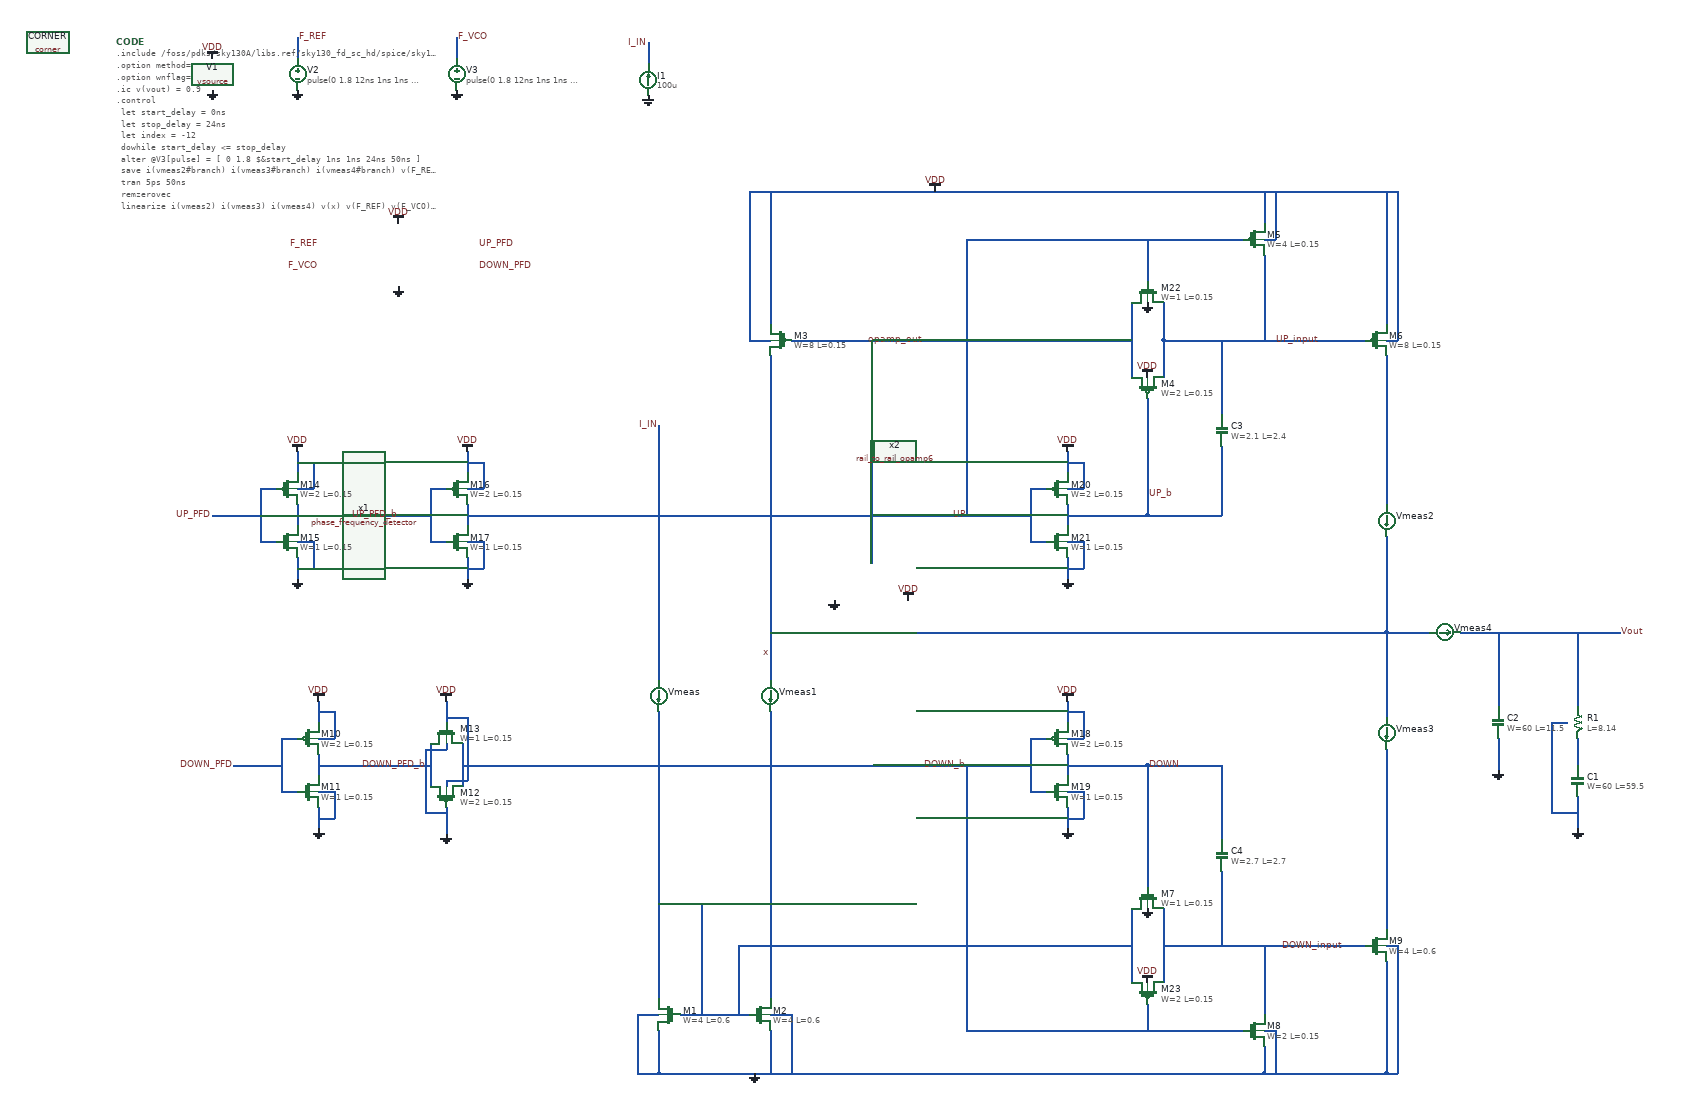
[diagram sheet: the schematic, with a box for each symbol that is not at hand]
v {xschem version=3.4.5 file_version=1.2
}
G {}
K {}
V {}
S {}
E {}
B 2 1210 -2170 2580 -1430 {flags=graph
y1=-0.00014
y2=0.00012
ypos1=0
ypos2=2
divy=5
subdivy=1
unity=1
x1=3.5340457e-07
x2=3.8858895e-07
divx=5
subdivx=1
xlabmag=1.0
ylabmag=1.0


dataset=0
unitx=1
logx=0
logy=0






color="11 5 6 12"
node="i(vmeas1)
i(vmeas2)
i(vmeas3)
\\"i(vmeas4)\\""
linewidth_mult=4
}
B 2 3350 -560 4770 220 {flags=graph
y1=-0.16
y2=1.9
ypos1=0
ypos2=2
divy=5
subdivy=1
unity=1
x1=3.5340457e-07
x2=3.8858895e-07
divx=5
subdivx=1
xlabmag=1.0
ylabmag=1.0


dataset=0
unitx=1
logx=0
logy=0








linewidth_mult=5





color="6 5"
node="up_pfd_b
down_pfd"}
B 2 3380 -1390 4760 -690 {flags=graph
y1=0
y2=0.01
ypos1=0
ypos2=2
divy=5
subdivy=1
unity=1
x1=3.5340457e-07
x2=3.8858895e-07
divx=5
subdivx=1
xlabmag=1.0
ylabmag=1.0


dataset=0
unitx=1
logx=0
logy=0








linewidth_mult=5

color="6 5"
node="up_pfd
down_pfd"}
B 2 4270 -2130 5120 -1470 {flags=graph
y1=0
y2=0.01
ypos1=0
ypos2=2
divy=5
subdivy=1
unity=1
x1=3.5340457e-07
x2=3.8858895e-07
divx=5
subdivx=1
xlabmag=1.0
ylabmag=1.0


dataset=0
unitx=1
logx=0
logy=0








linewidth_mult=5



color=6
node=vout}
B 2 2700 -2170 4070 -1430 {flags=graph
y1=0
y2=1.9
ypos1=0
ypos2=2
divy=5
subdivy=1
unity=1
x1=3.5340457e-07
x2=3.8858895e-07
divx=5
subdivx=1
xlabmag=1.0
ylabmag=1.0


dataset=0
unitx=1
logx=0
logy=0








linewidth_mult=4

color="6 7"
node="f_ref
f_vco"}
N 500 -1550 500 -1510 {
lab=F_REF}
N 800 -1550 800 -1510 {
lab=F_VCO}
N 1160 -1540 1160 -1500 {
lab=I_IN}
N 1220 290 1350 290 {
lab=#net1}
N 1180 320 1180 400 {
lab=GND}
N 1180 400 1680 400 {
lab=GND}
N 1140 290 1180 290 {
lab=GND}
N 1140 290 1140 400 {
lab=GND}
N 1140 400 1180 400 {
lab=GND}
N 1390 290 1430 290 {
lab=GND}
N 1350 -980 1390 -980 {
lab=VDD}
N 1680 400 1720 400 {
lab=GND}
N 1390 -1260 1390 -1010 {
lab=VDD}
N 1350 -1260 1350 -980 {
lab=VDD}
N 2550 -1260 2550 -1010 {
lab=VDD}
N 2320 -1260 2320 -1200 {
lab=VDD}
N 2320 -1170 2340 -1170 {
lab=VDD}
N 2340 -1260 2340 -1170 {
lab=VDD}
N 2570 -1260 2570 -980 {
lab=VDD}
N 2550 -980 2570 -980 {
lab=VDD}
N 2550 -950 2550 -670 {
lab=#net2}
N 1720 400 2320 400 {
lab=GND}
N 2320 350 2320 400 {
lab=GND}
N 2550 160 2570 160 {
lab=GND}
N 2550 400 2570 400 {
lab=GND}
N 600 -650 700 -650 {
lab=UP_PFD_b}
N 640 -180 750 -180 {
lab=DOWN_PFD_b}
N 340 -650 380 -650 {
lab=UP_PFD}
N 380 -180 420 -180 {
lab=DOWN_PFD}
N 1390 -950 1390 -550 {
lab=x}
N 1390 -430 1560 -430 {
lab=x}
N 1600 -430 2550 -430 {
lab=#net3}
N 1580 -980 1580 -560 {
lab=opamp_out}
N 2910 -230 2910 -180 {
lab=#net4}
N 2910 -430 2910 -290 {
lab=Vout}
N 2910 -120 2910 -60 {
lab=GND}
N 2860 -260 2890 -260 {
lab=GND}
N 2860 -260 2860 -90 {
lab=GND}
N 2860 -90 2910 -90 {
lab=GND}
N 2760 -430 2760 -290 {
lab=Vout}
N 2760 -230 2760 -170 {
lab=GND}
N 2690 -430 2990 -430 {
lab=Vout}
N 1260 80 1260 290 {
lab=#net1}
N 1180 80 1260 80 {
lab=#net1}
N 1430 290 1430 400 {
lab=GND}
N 1390 320 1390 400 {
lab=GND}
N 1330 160 2070 160 {
lab=#net1}
N 810 -180 1830 -180 {
lab=DOWN_b}
N 2100 -870 2100 -650 {
lab=UP_b}
N 1760 -1170 2280 -1170 {
lab=UP}
N 1760 -1170 1760 -650 {
lab=UP}
N 2320 -1140 2320 -980 {
lab=UP_input}
N 2130 -980 2510 -980 {
lab=UP_input}
N 1350 -1260 2570 -1260 {
lab=VDD}
N 2040 -180 2100 -180 {
lab=DOWN}
N 2100 -180 2100 50 {
lab=DOWN}
N 1760 -180 1760 320 {
lab=DOWN_b}
N 1760 320 2280 320 {
lab=DOWN_b}
N 750 -220 750 -140 {
lab=DOWN_PFD_b}
N 810 -220 810 -140 {
lab=DOWN_b}
N 780 -300 780 -260 {
lab=VDD}
N 780 -150 780 -140 {
lab=VDD}
N 780 -150 820 -150 {
lab=VDD}
N 820 -270 820 -150 {
lab=VDD}
N 780 -270 820 -270 {
lab=VDD}
N 780 -220 780 -210 {
lab=GND}
N 740 -210 780 -210 {
lab=GND}
N 740 -210 740 -90 {
lab=GND}
N 740 -90 780 -90 {
lab=GND}
N 780 -100 780 -50 {
lab=GND}
N 540 -200 540 -160 {
lab=DOWN_PFD_b}
N 470 -230 500 -230 {
lab=DOWN_PFD}
N 470 -230 470 -130 {
lab=DOWN_PFD}
N 470 -130 500 -130 {
lab=DOWN_PFD}
N 540 -180 640 -180 {
lab=DOWN_PFD_b}
N 420 -180 470 -180 {
lab=DOWN_PFD}
N 540 -100 540 -60 {
lab=GND}
N 540 -300 540 -260 {
lab=VDD}
N 540 -230 570 -230 {
lab=VDD}
N 570 -280 570 -230 {
lab=VDD}
N 540 -280 570 -280 {
lab=VDD}
N 540 -130 570 -130 {
lab=GND}
N 570 -130 570 -80 {
lab=GND}
N 540 -80 570 -80 {
lab=GND}
N 500 -670 500 -630 {
lab=UP_PFD_b}
N 430 -700 460 -700 {
lab=UP_PFD}
N 430 -700 430 -600 {
lab=UP_PFD}
N 430 -600 460 -600 {
lab=UP_PFD}
N 500 -650 600 -650 {
lab=UP_PFD_b}
N 380 -650 430 -650 {
lab=UP_PFD}
N 500 -570 500 -530 {
lab=GND}
N 500 -770 500 -730 {
lab=VDD}
N 500 -700 530 -700 {
lab=VDD}
N 530 -750 530 -700 {
lab=VDD}
N 500 -750 530 -750 {
lab=VDD}
N 500 -600 530 -600 {
lab=GND}
N 530 -600 530 -550 {
lab=GND}
N 500 -550 530 -550 {
lab=GND}
N 820 -670 820 -630 {
lab=UP}
N 750 -700 780 -700 {
lab=UP_PFD_b}
N 750 -700 750 -600 {
lab=UP_PFD_b}
N 750 -600 780 -600 {
lab=UP_PFD_b}
N 700 -650 750 -650 {
lab=UP_PFD_b}
N 820 -570 820 -530 {
lab=GND}
N 820 -770 820 -730 {
lab=VDD}
N 820 -700 850 -700 {
lab=VDD}
N 850 -750 850 -700 {
lab=VDD}
N 820 -750 850 -750 {
lab=VDD}
N 820 -600 850 -600 {
lab=GND}
N 850 -600 850 -550 {
lab=GND}
N 820 -550 850 -550 {
lab=GND}
N 1950 -200 1950 -160 {
lab=DOWN}
N 1880 -230 1910 -230 {
lab=DOWN_b}
N 1880 -230 1880 -130 {
lab=DOWN_b}
N 1880 -130 1910 -130 {
lab=DOWN_b}
N 1830 -180 1880 -180 {
lab=DOWN_b}
N 1950 -100 1950 -60 {
lab=GND}
N 1950 -300 1950 -260 {
lab=VDD}
N 1950 -230 1980 -230 {
lab=VDD}
N 1980 -280 1980 -230 {
lab=VDD}
N 1950 -280 1980 -280 {
lab=VDD}
N 1950 -130 1980 -130 {
lab=GND}
N 1980 -130 1980 -80 {
lab=GND}
N 1950 -80 1980 -80 {
lab=GND}
N 1950 -180 2040 -180 {
lab=DOWN}
N 1950 -670 1950 -630 {
lab=UP_b}
N 1880 -700 1910 -700 {
lab=UP}
N 1880 -700 1880 -600 {
lab=UP}
N 1880 -600 1910 -600 {
lab=UP}
N 1760 -650 1880 -650 {
lab=UP}
N 1950 -570 1950 -530 {
lab=GND}
N 1950 -770 1950 -730 {
lab=VDD}
N 1950 -700 1980 -700 {
lab=VDD}
N 1980 -750 1980 -700 {
lab=VDD}
N 1950 -750 1980 -750 {
lab=VDD}
N 1950 -600 1980 -600 {
lab=GND}
N 1980 -600 1980 -550 {
lab=GND}
N 1950 -550 1980 -550 {
lab=GND}
N 1950 -650 2040 -650 {
lab=UP_b}
N 2040 -650 2100 -650 {
lab=UP_b}
N 820 -650 1760 -650 {
lab=UP}
N 1390 -550 1390 -490 {
lab=x}
N 1180 -820 1180 -340 {
lab=I_IN}
N 1390 -490 1390 -340 {
lab=x}
N 1390 40 1390 260 {
lab=#net5}
N 1390 -280 1390 -20 {
lab=#net5}
N 1180 -280 1180 -20 {
lab=#net1}
N 1180 40 1180 260 {
lab=#net1}
N 1390 -20 1390 40 {
lab=#net5}
N 1180 -20 1180 40 {
lab=#net1}
N 2130 -1050 2130 -980 {
lab=UP_input}
N 2070 -1050 2070 -910 {
lab=opamp_out}
N 2130 -980 2130 -910 {
lab=UP_input}
N 1430 -980 2070 -980 {
lab=opamp_out}
N 2320 400 2550 400 {
lab=GND}
N 2130 90 2130 230 {
lab=DOWN_input}
N 2070 90 2070 230 {
lab=#net1}
N 2130 160 2510 160 {
lab=DOWN_input}
N 2550 190 2550 400 {
lab=GND}
N 2570 160 2570 400 {
lab=GND}
N 1330 160 1330 290 {
lab=#net1}
N 2320 160 2320 290 {
lab=DOWN_input}
N 2320 320 2340 320 {
lab=GND}
N 2340 320 2340 400 {
lab=GND}
N 2100 270 2100 320 {
lab=DOWN_b}
N 2100 -1170 2100 -1090 {
lab=UP}
N 2550 -210 2550 130 {
lab=#net6}
N 2550 -430 2550 -270 {
lab=#net3}
N 2550 -610 2550 -430 {
lab=#net3}
N 2100 -650 2240 -650 {
lab=UP_b}
N 2240 -780 2240 -650 {
lab=UP_b}
N 2240 -980 2240 -840 {
lab=UP_input}
N 2240 -180 2240 -40 {
lab=DOWN}
N 2240 20 2240 160 {
lab=DOWN_input}
N 2100 -180 2240 -180 {
lab=DOWN}
N 2550 -430 2630 -430 {
lab=#net3}
C {sky130_fd_pr/corner.sym} 30 -1540 0 0 {name=CORNER only_toplevel=false corner=tt}
C {devices/code.sym} 160 -1541.25 0 0 {name=CODE only_toplevel=false value="

.include /foss/pdks/sky130A/libs.ref/sky130_fd_sc_hd/spice/sky130_fd_sc_hd.spice

.option method=gear
.option wnflag=1

.ic v(vout) = 0.9

.control
  let start_delay = 0ns
  let stop_delay = 24ns
  let index = -12
  dowhile start_delay <= stop_delay
    
    alter @V3[pulse] = [ 0 1.8 $&start_delay 1ns 1ns 24ns 50ns ]
    save i(vmeas2#branch) i(vmeas3#branch) i(vmeas4#branch) v(F_REF) v(F_VCO) v(vout)
    tran 5ps 50ns
    remzerovec
    linearize i(vmeas2) i(vmeas3) i(vmeas4) v(x) v(F_REF) v(F_VCO) v(vout)
    echo $&start_delay
    write pfd_charge_pump_dead_zone_check_3_\{$&index\}.raw
    wrdata /foss/designs/my_design/projects/pll/charge_pump/xschem_ngspice/pfd_charge_pump_dead_zone_check_3_\{$&index\}.txt i(vmeas4)
    set appendwrite
    reset
    let index = index + 1
    let start_delay = start_delay + 1ns
  
  end
.endc

"}
C {devices/vsource.sym} 340 -1480 0 0 {name=V1 value=1.8 savecurrent=false}
C {devices/gnd.sym} 340 -1450 0 0 {name=l4 lab=GND}
C {devices/vdd.sym} 340 -1510 0 1 {name=l5 lab=VDD}
C {devices/vsource.sym} 500 -1480 0 0 {name=V2 value="pulse(0 1.8 12ns 1ns 1ns 24ns 50ns)" savecurrent=false
}
C {devices/gnd.sym} 500 -1450 0 0 {name=l7 lab=GND}
C {devices/lab_pin.sym} 500 -1550 0 1 {name=p1 sig_type=std_logic lab=F_REF}
C {devices/vsource.sym} 800 -1480 0 0 {name=V3 value="pulse(0 1.8 12ns 1ns 1ns 24ns 50ns)" savecurrent=false
* "sin(0.9 0.9 20.1MEG)" pulse(0 1.8 12ns 0.25ns 0.25ns 25ns 50ns)}
C {devices/gnd.sym} 800 -1450 0 0 {name=l11 lab=GND}
C {devices/lab_pin.sym} 800 -1550 0 1 {name=p2 sig_type=std_logic lab=F_VCO}
C {/foss/designs/my_design/projects/pll/pfd/xschem_ngspice/phase_frequency_detector.sym} 690 -1140 0 0 {name=x1}
C {devices/lab_pin.sym} 540 -1160 0 0 {name=p3 lab=F_REF}
C {devices/lab_pin.sym} 540 -1120 0 0 {name=p4 lab=F_VCO}
C {devices/lab_wire.sym} 840 -1160 0 1 {name=p5 sig_type=std_logic lab=UP_PFD}
C {devices/lab_wire.sym} 840 -1120 2 0 {name=p6 sig_type=std_logic lab=DOWN_PFD}
C {devices/gnd.sym} 690 -1080 0 0 {name=l12 lab=GND}
C {devices/vdd.sym} 690 -1200 0 1 {name=l13 lab=VDD}
C {devices/isource.sym} 1160 -1470 2 0 {name=I1 value=100u}
C {devices/gnd.sym} 1160 -1440 0 0 {name=l14 lab=GND}
C {devices/lab_pin.sym} 1160 -1540 2 1 {name=p7 sig_type=std_logic lab=I_IN}
C {sky130_fd_pr/nfet_01v8.sym} 1200 290 0 1 {name=M1
L=0.6
W=4
nf=1 
mult=1
ad="'int((nf+1)/2) * W/nf * 0.29'" 
pd="'2*int((nf+1)/2) * (W/nf + 0.29)'"
as="'int((nf+2)/2) * W/nf * 0.29'" 
ps="'2*int((nf+2)/2) * (W/nf + 0.29)'"
nrd="'0.29 / W'" nrs="'0.29 / W'"
sa=0 sb=0 sd=0
model=nfet_01v8
spiceprefix=X
}
C {sky130_fd_pr/nfet_01v8.sym} 1370 290 0 0 {name=M2
L=0.6
W=4
nf=1 
mult=1
ad="'int((nf+1)/2) * W/nf * 0.29'" 
pd="'2*int((nf+1)/2) * (W/nf + 0.29)'"
as="'int((nf+2)/2) * W/nf * 0.29'" 
ps="'2*int((nf+2)/2) * (W/nf + 0.29)'"
nrd="'0.29 / W'" nrs="'0.29 / W'"
sa=0 sb=0 sd=0
model=nfet_01v8
spiceprefix=X
}
C {sky130_fd_pr/pfet_01v8.sym} 1410 -980 2 0 {name=M3
L=0.15
W=8
nf=8
mult=1
ad="'int((nf+1)/2) * W/nf * 0.29'" 
pd="'2*int((nf+1)/2) * (W/nf + 0.29)'"
as="'int((nf+2)/2) * W/nf * 0.29'" 
ps="'2*int((nf+2)/2) * (W/nf + 0.29)'"
nrd="'0.29 / W'" nrs="'0.29 / W'"
sa=0 sb=0 sd=0
model=pfet_01v8
spiceprefix=X
}
C {devices/vdd.sym} 1700 -1260 0 0 {name=l1 lab=VDD}
C {devices/gnd.sym} 1360 400 0 0 {name=l2 lab=GND}
C {devices/lab_wire.sym} 1390 -390 0 0 {name=p8 sig_type=std_logic lab=x}
C {sky130_fd_pr/pfet_01v8.sym} 2100 -890 3 0 {name=M4
L=0.15
W=2
nf=2
mult=1
ad="'int((nf+1)/2) * W/nf * 0.29'" 
pd="'2*int((nf+1)/2) * (W/nf + 0.29)'"
as="'int((nf+2)/2) * W/nf * 0.29'" 
ps="'2*int((nf+2)/2) * (W/nf + 0.29)'"
nrd="'0.29 / W'" nrs="'0.29 / W'"
sa=0 sb=0 sd=0
model=pfet_01v8
spiceprefix=X
}
C {sky130_fd_pr/pfet_01v8.sym} 2300 -1170 0 0 {name=M5
L=0.15
W=4
nf=4
mult=1
ad="'int((nf+1)/2) * W/nf * 0.29'" 
pd="'2*int((nf+1)/2) * (W/nf + 0.29)'"
as="'int((nf+2)/2) * W/nf * 0.29'" 
ps="'2*int((nf+2)/2) * (W/nf + 0.29)'"
nrd="'0.29 / W'" nrs="'0.29 / W'"
sa=0 sb=0 sd=0
model=pfet_01v8
spiceprefix=X
}
C {sky130_fd_pr/pfet_01v8.sym} 2530 -980 0 0 {name=M6
L=0.15
W=8
nf=8
mult=1
ad="'int((nf+1)/2) * W/nf * 0.29'" 
pd="'2*int((nf+1)/2) * (W/nf + 0.29)'"
as="'int((nf+2)/2) * W/nf * 0.29'" 
ps="'2*int((nf+2)/2) * (W/nf + 0.29)'"
nrd="'0.29 / W'" nrs="'0.29 / W'"
sa=0 sb=0 sd=0
model=pfet_01v8
spiceprefix=X
}
C {devices/lab_wire.sym} 1760 -650 2 1 {name=p9 sig_type=std_logic lab=UP}
C {devices/lab_wire.sym} 2100 -690 0 1 {name=p10 sig_type=std_logic lab=UP_b}
C {sky130_fd_pr/nfet_01v8.sym} 2100 70 1 0 {name=M7
L=0.15
W=1
nf=1 
mult=1
ad="'int((nf+1)/2) * W/nf * 0.29'" 
pd="'2*int((nf+1)/2) * (W/nf + 0.29)'"
as="'int((nf+2)/2) * W/nf * 0.29'" 
ps="'2*int((nf+2)/2) * (W/nf + 0.29)'"
nrd="'0.29 / W'" nrs="'0.29 / W'"
sa=0 sb=0 sd=0
model=nfet_01v8
spiceprefix=X
}
C {sky130_fd_pr/nfet_01v8.sym} 2300 320 0 0 {name=M8
L=0.15
W=2
nf=2 
mult=1
ad="'int((nf+1)/2) * W/nf * 0.29'" 
pd="'2*int((nf+1)/2) * (W/nf + 0.29)'"
as="'int((nf+2)/2) * W/nf * 0.29'" 
ps="'2*int((nf+2)/2) * (W/nf + 0.29)'"
nrd="'0.29 / W'" nrs="'0.29 / W'"
sa=0 sb=0 sd=0
model=nfet_01v8
spiceprefix=X
}
C {devices/lab_wire.sym} 1760 -180 0 0 {name=p11 sig_type=std_logic lab=DOWN_b}
C {sky130_fd_pr/nfet_01v8.sym} 2530 160 0 0 {name=M9
L=0.6
W=4
nf=1 
mult=1
ad="'int((nf+1)/2) * W/nf * 0.29'" 
pd="'2*int((nf+1)/2) * (W/nf + 0.29)'"
as="'int((nf+2)/2) * W/nf * 0.29'" 
ps="'2*int((nf+2)/2) * (W/nf + 0.29)'"
nrd="'0.29 / W'" nrs="'0.29 / W'"
sa=0 sb=0 sd=0
model=nfet_01v8
spiceprefix=X
}
C {devices/lab_wire.sym} 600 -650 0 1 {name=p15 sig_type=std_logic lab=UP_PFD_b}
C {devices/lab_wire.sym} 2340 -980 2 0 {name=p13 sig_type=std_logic lab=UP_input}
C {devices/lab_wire.sym} 2470 160 0 0 {name=p14 sig_type=std_logic lab=DOWN_input}
C {devices/gnd.sym} 1510 -490 0 1 {name=l3 lab=GND}
C {devices/lab_wire.sym} 1680 -980 0 0 {name=p17 sig_type=std_logic lab=opamp_out}
C {devices/lab_wire.sym} 2990 -430 0 1 {name=p12 sig_type=std_logic lab=Vout}
C {devices/lab_wire.sym} 340 -650 0 0 {name=p16 sig_type=std_logic lab=UP_PFD}
C {devices/lab_wire.sym} 380 -180 2 1 {name=p18 sig_type=std_logic lab=DOWN_PFD}
C {sky130_fd_pr/cap_mim_m3_1.sym} 2760 -260 0 0 {name=C2 model=cap_mim_m3_1 W=60 L=11.5 MF=1 spiceprefix=X}
C {sky130_fd_pr/cap_mim_m3_1.sym} 2910 -150 0 0 {name=C1 model=cap_mim_m3_1 W=60 L=59.5 MF=1 spiceprefix=X}
C {devices/gnd.sym} 2910 -60 0 0 {name=l6 lab=GND}
C {devices/gnd.sym} 2760 -170 0 0 {name=l9 lab=GND
W=60}
C {/foss/designs/my_design/projects/pll/charge_pump/xschem_ngspice/rail_to_rail_opamp6.sym} 1580 -490 1 1 {name=x2}
C {devices/vdd.sym} 1650 -490 0 0 {name=l8 lab=VDD}
C {sky130_fd_pr/res_xhigh_po_0p35.sym} 2910 -260 0 0 {name=R1
L=8.14
model=res_xhigh_po_0p35
spiceprefix=X
mult=1}
C {sky130_fd_pr/pfet_01v8.sym} 780 -120 3 0 {name=M12
L=0.15
W=2
nf=2
mult=1
ad="'int((nf+1)/2) * W/nf * 0.29'" 
pd="'2*int((nf+1)/2) * (W/nf + 0.29)'"
as="'int((nf+2)/2) * W/nf * 0.29'" 
ps="'2*int((nf+2)/2) * (W/nf + 0.29)'"
nrd="'0.29 / W'" nrs="'0.29 / W'"
sa=0 sb=0 sd=0
model=pfet_01v8
spiceprefix=X
}
C {sky130_fd_pr/nfet_01v8.sym} 780 -240 1 0 {name=M13
L=0.15
W=1
nf=1 
mult=1
ad="'int((nf+1)/2) * W/nf * 0.29'" 
pd="'2*int((nf+1)/2) * (W/nf + 0.29)'"
as="'int((nf+2)/2) * W/nf * 0.29'" 
ps="'2*int((nf+2)/2) * (W/nf + 0.29)'"
nrd="'0.29 / W'" nrs="'0.29 / W'"
sa=0 sb=0 sd=0
model=nfet_01v8
spiceprefix=X
}
C {devices/vdd.sym} 780 -300 0 0 {name=l10 lab=VDD}
C {devices/gnd.sym} 780 -50 0 0 {name=l15 lab=GND}
C {sky130_fd_pr/pfet_01v8.sym} 520 -230 0 0 {name=M10
L=0.15
W=2
nf=2
mult=1
ad="'int((nf+1)/2) * W/nf * 0.29'" 
pd="'2*int((nf+1)/2) * (W/nf + 0.29)'"
as="'int((nf+2)/2) * W/nf * 0.29'" 
ps="'2*int((nf+2)/2) * (W/nf + 0.29)'"
nrd="'0.29 / W'" nrs="'0.29 / W'"
sa=0 sb=0 sd=0
model=pfet_01v8
spiceprefix=X
}
C {sky130_fd_pr/nfet_01v8.sym} 520 -130 2 1 {name=M11
L=0.15
W=1
nf=1 
mult=1
ad="'int((nf+1)/2) * W/nf * 0.29'" 
pd="'2*int((nf+1)/2) * (W/nf + 0.29)'"
as="'int((nf+2)/2) * W/nf * 0.29'" 
ps="'2*int((nf+2)/2) * (W/nf + 0.29)'"
nrd="'0.29 / W'" nrs="'0.29 / W'"
sa=0 sb=0 sd=0
model=nfet_01v8
spiceprefix=X
}
C {devices/gnd.sym} 540 -60 0 0 {name=l16 lab=GND}
C {devices/vdd.sym} 540 -300 0 0 {name=l17 lab=VDD}
C {sky130_fd_pr/pfet_01v8.sym} 480 -700 0 0 {name=M14
L=0.15
W=2
nf=2
mult=1
ad="'int((nf+1)/2) * W/nf * 0.29'" 
pd="'2*int((nf+1)/2) * (W/nf + 0.29)'"
as="'int((nf+2)/2) * W/nf * 0.29'" 
ps="'2*int((nf+2)/2) * (W/nf + 0.29)'"
nrd="'0.29 / W'" nrs="'0.29 / W'"
sa=0 sb=0 sd=0
model=pfet_01v8
spiceprefix=X
}
C {sky130_fd_pr/nfet_01v8.sym} 480 -600 2 1 {name=M15
L=0.15
W=1
nf=1 
mult=1
ad="'int((nf+1)/2) * W/nf * 0.29'" 
pd="'2*int((nf+1)/2) * (W/nf + 0.29)'"
as="'int((nf+2)/2) * W/nf * 0.29'" 
ps="'2*int((nf+2)/2) * (W/nf + 0.29)'"
nrd="'0.29 / W'" nrs="'0.29 / W'"
sa=0 sb=0 sd=0
model=nfet_01v8
spiceprefix=X
}
C {devices/gnd.sym} 500 -530 0 0 {name=l18 lab=GND}
C {devices/vdd.sym} 500 -770 0 0 {name=l19 lab=VDD}
C {sky130_fd_pr/pfet_01v8.sym} 800 -700 0 0 {name=M16
L=0.15
W=2
nf=2
mult=1
ad="'int((nf+1)/2) * W/nf * 0.29'" 
pd="'2*int((nf+1)/2) * (W/nf + 0.29)'"
as="'int((nf+2)/2) * W/nf * 0.29'" 
ps="'2*int((nf+2)/2) * (W/nf + 0.29)'"
nrd="'0.29 / W'" nrs="'0.29 / W'"
sa=0 sb=0 sd=0
model=pfet_01v8
spiceprefix=X
}
C {sky130_fd_pr/nfet_01v8.sym} 800 -600 2 1 {name=M17
L=0.15
W=1
nf=1 
mult=1
ad="'int((nf+1)/2) * W/nf * 0.29'" 
pd="'2*int((nf+1)/2) * (W/nf + 0.29)'"
as="'int((nf+2)/2) * W/nf * 0.29'" 
ps="'2*int((nf+2)/2) * (W/nf + 0.29)'"
nrd="'0.29 / W'" nrs="'0.29 / W'"
sa=0 sb=0 sd=0
model=nfet_01v8
spiceprefix=X
}
C {devices/gnd.sym} 820 -530 0 0 {name=l20 lab=GND}
C {devices/vdd.sym} 820 -770 0 0 {name=l21 lab=VDD}
C {sky130_fd_pr/pfet_01v8.sym} 1930 -230 0 0 {name=M18
L=0.15
W=2
nf=2
mult=1
ad="'int((nf+1)/2) * W/nf * 0.29'" 
pd="'2*int((nf+1)/2) * (W/nf + 0.29)'"
as="'int((nf+2)/2) * W/nf * 0.29'" 
ps="'2*int((nf+2)/2) * (W/nf + 0.29)'"
nrd="'0.29 / W'" nrs="'0.29 / W'"
sa=0 sb=0 sd=0
model=pfet_01v8
spiceprefix=X
}
C {sky130_fd_pr/nfet_01v8.sym} 1930 -130 2 1 {name=M19
L=0.15
W=1
nf=1 
mult=1
ad="'int((nf+1)/2) * W/nf * 0.29'" 
pd="'2*int((nf+1)/2) * (W/nf + 0.29)'"
as="'int((nf+2)/2) * W/nf * 0.29'" 
ps="'2*int((nf+2)/2) * (W/nf + 0.29)'"
nrd="'0.29 / W'" nrs="'0.29 / W'"
sa=0 sb=0 sd=0
model=nfet_01v8
spiceprefix=X
}
C {devices/gnd.sym} 1950 -60 0 0 {name=l22 lab=GND}
C {devices/vdd.sym} 1950 -300 0 0 {name=l23 lab=VDD}
C {sky130_fd_pr/pfet_01v8.sym} 1930 -700 0 0 {name=M20
L=0.15
W=2
nf=2
mult=1
ad="'int((nf+1)/2) * W/nf * 0.29'" 
pd="'2*int((nf+1)/2) * (W/nf + 0.29)'"
as="'int((nf+2)/2) * W/nf * 0.29'" 
ps="'2*int((nf+2)/2) * (W/nf + 0.29)'"
nrd="'0.29 / W'" nrs="'0.29 / W'"
sa=0 sb=0 sd=0
model=pfet_01v8
spiceprefix=X
}
C {sky130_fd_pr/nfet_01v8.sym} 1930 -600 2 1 {name=M21
L=0.15
W=1
nf=1 
mult=1
ad="'int((nf+1)/2) * W/nf * 0.29'" 
pd="'2*int((nf+1)/2) * (W/nf + 0.29)'"
as="'int((nf+2)/2) * W/nf * 0.29'" 
ps="'2*int((nf+2)/2) * (W/nf + 0.29)'"
nrd="'0.29 / W'" nrs="'0.29 / W'"
sa=0 sb=0 sd=0
model=nfet_01v8
spiceprefix=X
}
C {devices/gnd.sym} 1950 -530 0 0 {name=l24 lab=GND}
C {devices/vdd.sym} 1950 -770 0 0 {name=l25 lab=VDD}
C {devices/ammeter.sym} 1180 -310 0 0 {name=Vmeas savecurrent=true spice_ignore=0}
C {devices/ammeter.sym} 1390 -310 0 0 {name=Vmeas1 savecurrent=true spice_ignore=0}
C {devices/lab_wire.sym} 620 -180 2 0 {name=p20 sig_type=std_logic lab=DOWN_PFD_b}
C {devices/lab_wire.sym} 2100 -180 0 1 {name=p21 sig_type=std_logic lab=DOWN}
C {devices/ammeter.sym} 2550 -640 0 0 {name=Vmeas2 savecurrent=true spice_ignore=0}
C {devices/ammeter.sym} 2550 -240 0 0 {name=Vmeas3 savecurrent=true spice_ignore=0}
C {devices/ammeter.sym} 2660 -430 3 0 {name=Vmeas4 savecurrent=true spice_ignore=0}
C {sky130_fd_pr/nfet_01v8.sym} 2100 -1070 1 0 {name=M22
L=0.15
W=1
nf=1 
mult=1
ad="'int((nf+1)/2) * W/nf * 0.29'" 
pd="'2*int((nf+1)/2) * (W/nf + 0.29)'"
as="'int((nf+2)/2) * W/nf * 0.29'" 
ps="'2*int((nf+2)/2) * (W/nf + 0.29)'"
nrd="'0.29 / W'" nrs="'0.29 / W'"
sa=0 sb=0 sd=0
model=nfet_01v8
spiceprefix=X
}
C {sky130_fd_pr/pfet_01v8.sym} 2100 250 3 0 {name=M23
L=0.15
W=2
nf=2
mult=1
ad="'int((nf+1)/2) * W/nf * 0.29'" 
pd="'2*int((nf+1)/2) * (W/nf + 0.29)'"
as="'int((nf+2)/2) * W/nf * 0.29'" 
ps="'2*int((nf+2)/2) * (W/nf + 0.29)'"
nrd="'0.29 / W'" nrs="'0.29 / W'"
sa=0 sb=0 sd=0
model=pfet_01v8
spiceprefix=X
}
C {devices/vdd.sym} 2100 -910 0 0 {name=l26 lab=VDD}
C {devices/gnd.sym} 2100 -1050 0 0 {name=l27 lab=GND}
C {devices/gnd.sym} 2100 90 0 0 {name=l28 lab=GND}
C {devices/vdd.sym} 2100 230 0 0 {name=l29 lab=VDD}
C {sky130_fd_pr/cap_mim_m3_1.sym} 2240 -810 0 0 {name=C3 model=cap_mim_m3_1 W=2.1 L=2.4 MF=1 spiceprefix=X}
C {sky130_fd_pr/cap_mim_m3_1.sym} 2240 -10 0 0 {name=C4 model=cap_mim_m3_1 W=2.7 L=2.7 MF=1 spiceprefix=X}
C {devices/lab_pin.sym} 1180 -820 2 1 {name=p22 sig_type=std_logic lab=I_IN}
